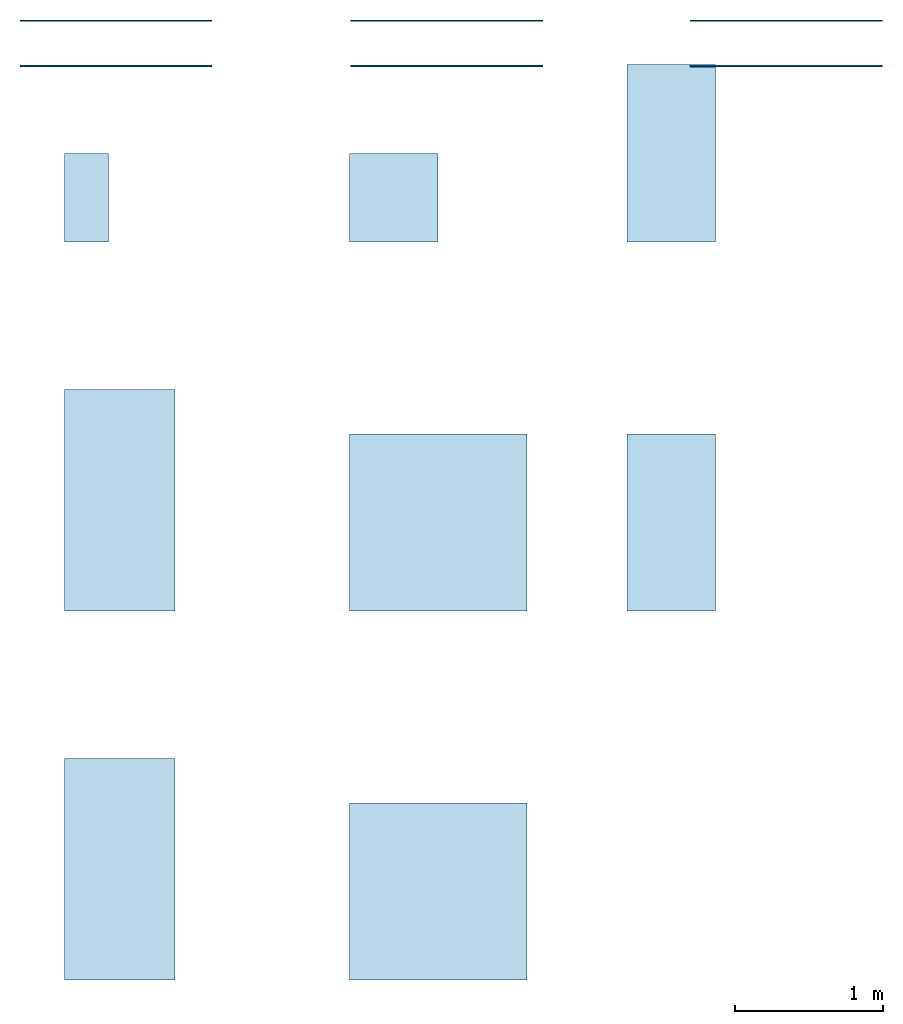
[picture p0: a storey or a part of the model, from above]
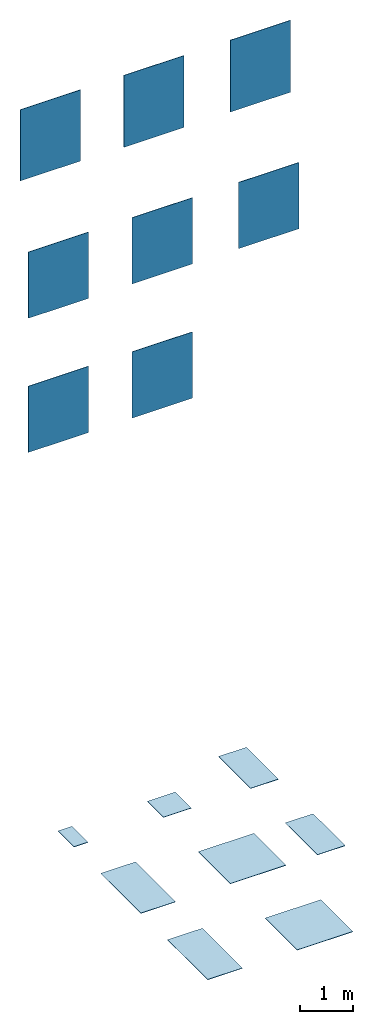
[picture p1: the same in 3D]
Properties of the parts of a building model (IFC2X3)

# File
Description: ViewDefinition [CoordinationView_V2.0], RevitIdentifiers [VersionGUID: 46d3328d-7286-4044-a276-93108096e048, NumberOfSaves: 353], CoordinateReference [CoordinateBase: Shared Coordinates, ProjectSite: Internal]
File name: Project Number
Time: 2025-03-24T15:53:54+01:00
Written by: ODA SDAI 24.3
Made in: Autodesk Revit 24.1.11.26 (ENU) - IFC 24.1.11.26

# IfcProject, Project Number
LongName: Refin-Blended; Phase: Project Status

# IfcSite, Default
RefLatitude: 51, 30, 0, 549316; RefLongitude: 0, -7, -34, -450321; RefElevation: 0 mm

# IfcBuilding
Pset_BuildingCommon - NumberOfStoreys: 1

# IfcBuildingStorey: Level:Circle Head - Project Datum (2)
Pset_AirSideSystemInformation - sets with these values: 2
Name | LongName = Name | Elevation (mm)
Level 0 | Level 0 | 0
Level 1 | Level 1 | 4000

# IfcSlab: Floor:Floor_Tiles_Refin-Etherea-Grey-120x120 RJ58, Floor:Floor_Tiles_Refin-Etherea-Grey-120x120 RJ58:357631
In: Level 0
Type - PredefinedType: FLOOR; Material: Etherea-Grey-120x120 RJ58 9 mm, <Unnamed> 1 mm
Type - Pset_ConcreteElementGeneral - FireRating: INERT
Type - Pset_ElementShading - Color: GREY
Type - Pset_FireRatingProperties - SurfaceSpreadOfFlame: INERT
Type - Pset_ManufacturerOccurrence - BarCode: N/A; SerialNumber: N/A
Type - Pset_ManufacturerTypeInformation - ArticleNumber: RJ58; ModelReference: RJ58; ModelLabel: GREY R 120X120; Manufacturer: info@refin.it; ProductionYear: N/A
Type - Pset_PrecastConcreteElementGeneral - SerialNumber: N/A
Type - Pset_ProductRequirements - Name: Etherea_Grey_120X120 R; Category: Pr_35_93_96_19:Ceramic tiles
Type - Pset_QuantityTakeOff - Reference: N/A
Type - Pset_ReinforcementBarPitchOfSlab - Description: PORCELAIN STONEWARE TILE; Reference: N/A
Type - Pset_SlabCommon - Reference: N/A; IsExternal: no; AcousticRating: N/A; FireRating: INERT; SurfaceSpreadOfFlame: INERT
Type - Pset_Warranty - WarrantyContent: N/A; Exclusions: N/A
Pset_QuantityTakeOff - sets with these values: 2
Pset_SlabCommon - LoadBearing: no; PitchAngle: 0 deg

# IfcSlab: Floor:Floor_Tiles_Refin-Etherea-Grey-30x60 RJ90, Floor:Floor_Tiles_Refin-Etherea-Grey-30x60 RJ90:304668
In: Level 0
Type - PredefinedType: FLOOR; Material: Etherea-Grey-30x60 RJ90 9 mm, <Unnamed> 1 mm
Type - Pset_ConcreteElementGeneral - FireRating: INERT
Type - Pset_ElementShading - Color: GREY
Type - Pset_FireRatingProperties - SurfaceSpreadOfFlame: INERT
Type - Pset_ManufacturerOccurrence - BarCode: N/A; SerialNumber: N/A
Type - Pset_ManufacturerTypeInformation - ArticleNumber: RJ90; ModelReference: RJ90; ModelLabel: GREY R 30X60; Manufacturer: info@refin.it; ProductionYear: N/A
Type - Pset_PrecastConcreteElementGeneral - SerialNumber: N/A
Type - Pset_ProductRequirements - Name: Etherea_Grey_30X60 R; Category: Pr_35_93_96_19:Ceramic tiles
Type - Pset_QuantityTakeOff - Reference: N/A
Type - Pset_ReinforcementBarPitchOfSlab - Description: PORCELAIN STONEWARE TILE; Reference: N/A
Type - Pset_SlabCommon - Reference: N/A; IsExternal: no; AcousticRating: N/A; FireRating: INERT; SurfaceSpreadOfFlame: INERT
Type - Pset_Warranty - WarrantyContent: N/A; Exclusions: N/A
Pset_QuantityTakeOff - sets with these values: 2
Pset_SlabCommon - LoadBearing: no; PitchAngle: 0 deg

# IfcSlab: Floor:Floor_Tiles_Refin-Etherea-Grey-60x120 RJ71, Floor:Floor_Tiles_Refin-Etherea-Grey-60x120 RJ71:357441
In: Level 0
Type - PredefinedType: FLOOR; Material: Etherea-Grey-60x120 RJ71 9 mm, <Unnamed> 1 mm
Type - Pset_ConcreteElementGeneral - FireRating: INERT
Type - Pset_ElementShading - Color: GREY
Type - Pset_FireRatingProperties - SurfaceSpreadOfFlame: INERT
Type - Pset_ManufacturerOccurrence - BarCode: N/A; SerialNumber: N/A
Type - Pset_ManufacturerTypeInformation - ArticleNumber: RJ71; ModelReference: RJ71; ModelLabel: GREY R 60X120; Manufacturer: info@refin.it; ProductionYear: N/A
Type - Pset_PrecastConcreteElementGeneral - SerialNumber: N/A
Type - Pset_ProductRequirements - Name: Etherea_Grey_60X120 R; Category: Pr_35_93_96_19:Ceramic tiles
Type - Pset_QuantityTakeOff - Reference: N/A
Type - Pset_ReinforcementBarPitchOfSlab - Description: PORCELAIN STONEWARE TILE; Reference: N/A
Type - Pset_SlabCommon - Reference: N/A; IsExternal: no; AcousticRating: N/A; FireRating: INERT; SurfaceSpreadOfFlame: INERT
Type - Pset_Warranty - WarrantyContent: N/A; Exclusions: N/A
Pset_QuantityTakeOff - sets with these values: 2
Pset_SlabCommon - LoadBearing: no; PitchAngle: 0 deg

# IfcSlab: Floor:Floor_Tiles_Refin-Etherea-Grey-60x60 RJ85, Floor:Floor_Tiles_Refin-Etherea-Grey-60x60 RJ85:357245
In: Level 0
Type - PredefinedType: FLOOR; Material: Etherea-Grey-60x60 RJ85 9 mm, <Unnamed> 1 mm
Type - Pset_ConcreteElementGeneral - FireRating: INERT
Type - Pset_ElementShading - Color: GREY
Type - Pset_FireRatingProperties - SurfaceSpreadOfFlame: INERT
Type - Pset_ManufacturerOccurrence - BarCode: N/A; SerialNumber: N/A
Type - Pset_ManufacturerTypeInformation - ArticleNumber: RJ85; ModelReference: RJ85; ModelLabel: GREY R 60X60; Manufacturer: info@refin.it; ProductionYear: N/A
Type - Pset_PrecastConcreteElementGeneral - SerialNumber: N/A
Type - Pset_ProductRequirements - Name: Etherea_Grey_60X60 R; Category: Pr_35_93_96_19:Ceramic tiles
Type - Pset_QuantityTakeOff - Reference: N/A
Type - Pset_ReinforcementBarPitchOfSlab - Description: PORCELAIN STONEWARE TILE; Reference: N/A
Type - Pset_SlabCommon - Reference: N/A; IsExternal: no; AcousticRating: N/A; FireRating: INERT; SurfaceSpreadOfFlame: INERT
Type - Pset_Warranty - WarrantyContent: N/A; Exclusions: N/A
Pset_QuantityTakeOff - sets with these values: 2
Pset_SlabCommon - LoadBearing: no; PitchAngle: 0 deg

# IfcSlab: Floor:Floor_Tiles_Refin-Etherea-Grey-75x150 RK14, Floor:Floor_Tiles_Refin-Etherea-Grey-75x150 RK14:357623
In: Level 0
Type - PredefinedType: FLOOR; Material: Etherea-Grey-75x150 RK14 9 mm, <Unnamed> 1 mm
Type - Pset_ConcreteElementGeneral - FireRating: INERT
Type - Pset_ElementShading - Color: GREY
Type - Pset_FireRatingProperties - SurfaceSpreadOfFlame: INERT
Type - Pset_ManufacturerOccurrence - BarCode: N/A; SerialNumber: N/A
Type - Pset_ManufacturerTypeInformation - ArticleNumber: RK14; ModelReference: RK14; ModelLabel: GREY R 75X150; Manufacturer: info@refin.it; ProductionYear: N/A
Type - Pset_PrecastConcreteElementGeneral - SerialNumber: N/A
Type - Pset_ProductRequirements - Name: Etherea_Grey_75X150 R; Category: Pr_35_93_96_19:Ceramic tiles
Type - Pset_QuantityTakeOff - Reference: N/A
Type - Pset_ReinforcementBarPitchOfSlab - Description: PORCELAIN STONEWARE TILE; Reference: N/A
Type - Pset_SlabCommon - Reference: N/A; IsExternal: no; AcousticRating: N/A; FireRating: INERT; SurfaceSpreadOfFlame: INERT
Type - Pset_Warranty - WarrantyContent: N/A; Exclusions: N/A
Pset_QuantityTakeOff - sets with these values: 2
Pset_SlabCommon - LoadBearing: no; PitchAngle: 0 deg

# IfcSlab: Floor:Floor_Tiles_Refin-Etherea-Grey-C2-GRIP-60x120 RN15, Floor:Floor_Tiles_Refin-Etherea-Grey-C2-GRIP-60x120 RN15:357639
In: Level 0
Type - PredefinedType: FLOOR; Material: Etherea-Grey-C2-GRIP-60x120 RN15 9 mm, <Unnamed> 1 mm
Type - Pset_ConcreteElementGeneral - FireRating: INERT
Type - Pset_ElementShading - Color: GREY
Type - Pset_FireRatingProperties - SurfaceSpreadOfFlame: INERT
Type - Pset_ManufacturerOccurrence - BarCode: N/A; SerialNumber: N/A
Type - Pset_ManufacturerTypeInformation - ArticleNumber: RN15; ModelReference: RN15; ModelLabel: GREY C2 GRIP R 60X120; Manufacturer: info@refin.it; ProductionYear: N/A
Type - Pset_PrecastConcreteElementGeneral - SerialNumber: N/A
Type - Pset_ProductRequirements - Name: Etherea_Grey_C2_GRIP_60X120 R; Category: Pr_35_93_96_19:Ceramic tiles
Type - Pset_QuantityTakeOff - Reference: N/A
Type - Pset_ReinforcementBarPitchOfSlab - Description: PORCELAIN STONEWARE TILE; Reference: N/A
Type - Pset_SlabCommon - Reference: N/A; IsExternal: no; AcousticRating: N/A; FireRating: INERT; SurfaceSpreadOfFlame: INERT
Type - Pset_Warranty - WarrantyContent: N/A; Exclusions: N/A
Pset_QuantityTakeOff - sets with these values: 2
Pset_SlabCommon - LoadBearing: no; PitchAngle: 0 deg

# IfcSlab: Floor:Floor_Tiles_Refin-Etherea-Grey-Lucido-120x120 RJ62, Floor:Floor_Tiles_Refin-Etherea-Grey-Lucido-120x120 RJ62:361557
In: Level 0
Type - PredefinedType: FLOOR; Material: Etherea-Grey-Lucido-120x120 RJ62 9 mm, <Unnamed> 1 mm
Type - Pset_ConcreteElementGeneral - FireRating: INERT
Type - Pset_ElementShading - Color: GREY
Type - Pset_FireRatingProperties - SurfaceSpreadOfFlame: INERT
Type - Pset_ManufacturerOccurrence - BarCode: N/A; SerialNumber: N/A
Type - Pset_ManufacturerTypeInformation - ArticleNumber: RJ62; ModelReference: RJ62; ModelLabel: GREY LUCIDO R 120X120; Manufacturer: info@refin.it; ProductionYear: N/A
Type - Pset_PrecastConcreteElementGeneral - SerialNumber: N/A
Type - Pset_ProductRequirements - Name: Etherea_Grey_Lucido_120X120 R; Category: Pr_35_93_96_19:Ceramic tiles
Type - Pset_QuantityTakeOff - Reference: N/A
Type - Pset_ReinforcementBarPitchOfSlab - Description: PORCELAIN STONEWARE TILE; Reference: N/A
Type - Pset_SlabCommon - Reference: N/A; IsExternal: no; AcousticRating: N/A; FireRating: INERT; SurfaceSpreadOfFlame: INERT
Type - Pset_Warranty - WarrantyContent: N/A; Exclusions: N/A
Pset_QuantityTakeOff - sets with these values: 2
Pset_SlabCommon - LoadBearing: no; PitchAngle: 0 deg

# IfcSlab: Floor:Floor_Tiles_Refin-Etherea-Grey-Lucido-75x150 RK19, Floor:Floor_Tiles_Refin-Etherea-Grey-Lucido-75x150 RK19:361417
In: Level 0
Type - PredefinedType: FLOOR; Material: Etherea-Grey-Lucido-75x150 RK19 9 mm, <Unnamed> 1 mm
Type - Pset_ConcreteElementGeneral - FireRating: INERT
Type - Pset_ElementShading - Color: GREY
Type - Pset_FireRatingProperties - SurfaceSpreadOfFlame: INERT
Type - Pset_ManufacturerOccurrence - BarCode: N/A; SerialNumber: N/A
Type - Pset_ManufacturerTypeInformation - ArticleNumber: RK19; ModelReference: RK19; ModelLabel: GREY LUCIDO R 75X150; Manufacturer: info@refin.it; ProductionYear: N/A
Type - Pset_PrecastConcreteElementGeneral - SerialNumber: N/A
Type - Pset_ProductRequirements - Name: Etherea_Grey_Lucido_75X150 R; Category: Pr_35_93_96_19:Ceramic tiles
Type - Pset_QuantityTakeOff - Reference: N/A
Type - Pset_ReinforcementBarPitchOfSlab - Description: PORCELAIN STONEWARE TILE; Reference: N/A
Type - Pset_SlabCommon - Reference: N/A; IsExternal: no; AcousticRating: N/A; FireRating: INERT; SurfaceSpreadOfFlame: INERT
Type - Pset_Warranty - WarrantyContent: N/A; Exclusions: N/A
Pset_QuantityTakeOff - sets with these values: 2
Pset_SlabCommon - LoadBearing: no; PitchAngle: 0 deg

# IfcWallStandardCase: Basic Wall:Wall_Tiles_Refin-Etherea-Grey-120x120 RJ58, Basic Wall:Wall_Tiles_Refin-Etherea-Grey-120x120 RJ58:335490
In: Level 0
Type - PredefinedType: STANDARD; Material: <Unnamed> 1 mm, Etherea-Grey-120x120 RJ58 9 mm
Type - Pset_ElementShading - Color: GREY
Type - Pset_FireRatingProperties - SurfaceSpreadOfFlame: INERT
Type - Pset_ManufacturerOccurrence - BarCode: N/A; SerialNumber: N/A
Type - Pset_ManufacturerTypeInformation - ArticleNumber: RJ58; ModelReference: RJ58; ModelLabel: GREY R 120X120; Manufacturer: info@refin.it; ProductionYear: N/A
Type - Pset_PrecastConcreteElementGeneral - SerialNumber: N/A
Type - Pset_ProductRequirements - Name: Etherea_Grey_120X120 R; Category: Pr_35_93_96_19:Ceramic tiles
Type - Pset_QuantityTakeOff - Reference: N/A
Type - Pset_ReinforcementBarPitchOfWall - Description: PORCELAIN STONEWARE TILE; Reference: N/A
Type - Pset_WallCommon - Reference: N/A; IsExternal: no; AcousticRating: N/A; SurfaceSpreadOfFlame: INERT
Type - Pset_Warranty - WarrantyContent: N/A; Exclusions: N/A
Pset_QuantityTakeOff - sets with these values: 2
Pset_WallCommon - LoadBearing: no; ExtendToStructure: no

# IfcWallStandardCase: Basic Wall:Wall_Tiles_Refin-Etherea-Grey-30x60 RJ90, Basic Wall:Wall_Tiles_Refin-Etherea-Grey-30x60 RJ90:334895
In: Level 0
Type - PredefinedType: STANDARD; Material: <Unnamed> 1 mm, Etherea-Grey-30x60 RJ90 9 mm
Type - Pset_ElementShading - Color: GREY
Type - Pset_FireRatingProperties - SurfaceSpreadOfFlame: INERT
Type - Pset_ManufacturerOccurrence - BarCode: N/A; SerialNumber: N/A
Type - Pset_ManufacturerTypeInformation - ArticleNumber: RJ90; ModelReference: RJ90; ModelLabel: GREY R 30X60; Manufacturer: info@refin.it; ProductionYear: N/A
Type - Pset_PrecastConcreteElementGeneral - SerialNumber: N/A
Type - Pset_ProductRequirements - Name: Etherea_Grey_30X60 R; Category: Pr_35_93_96_19:Ceramic tiles
Type - Pset_QuantityTakeOff - Reference: N/A
Type - Pset_ReinforcementBarPitchOfWall - Description: PORCELAIN STONEWARE TILE; Reference: N/A
Type - Pset_WallCommon - Reference: N/A; IsExternal: no; AcousticRating: N/A; SurfaceSpreadOfFlame: INERT
Type - Pset_Warranty - WarrantyContent: N/A; Exclusions: N/A
Pset_QuantityTakeOff - sets with these values: 2
Pset_WallCommon - LoadBearing: no; ExtendToStructure: no

# IfcWallStandardCase: Basic Wall:Wall_Tiles_Refin-Etherea-Grey-60x120 RJ71, Basic Wall:Wall_Tiles_Refin-Etherea-Grey-60x120 RJ71:334553
In: Level 0
Type - PredefinedType: STANDARD; Material: <Unnamed> 1 mm, Etherea-Grey-60x120 RJ71 9 mm
Type - Pset_ElementShading - Color: GREY
Type - Pset_FireRatingProperties - SurfaceSpreadOfFlame: INERT
Type - Pset_ManufacturerOccurrence - BarCode: N/A; SerialNumber: N/A
Type - Pset_ManufacturerTypeInformation - ArticleNumber: RJ71; ModelReference: RJ71; ModelLabel: GREY R 60X120; Manufacturer: info@refin.it; ProductionYear: N/A
Type - Pset_PrecastConcreteElementGeneral - SerialNumber: N/A
Type - Pset_ProductRequirements - Name: Etherea_Grey_60X120 R; Category: Pr_35_93_96_19:Ceramic tiles
Type - Pset_QuantityTakeOff - Reference: N/A
Type - Pset_ReinforcementBarPitchOfWall - Description: PORCELAIN STONEWARE TILE; Reference: N/A
Type - Pset_WallCommon - Reference: N/A; IsExternal: no; AcousticRating: N/A; SurfaceSpreadOfFlame: INERT
Type - Pset_Warranty - WarrantyContent: N/A; Exclusions: N/A
Pset_QuantityTakeOff - sets with these values: 2
Pset_WallCommon - LoadBearing: no; ExtendToStructure: no

# IfcWallStandardCase: Basic Wall:Wall_Tiles_Refin-Etherea-Grey-60x60 RJ85, Basic Wall:Wall_Tiles_Refin-Etherea-Grey-60x60 RJ85:333696
In: Level 0
Type - PredefinedType: STANDARD; Material: <Unnamed> 1 mm, Etherea-Grey-60x60 RJ85 9 mm
Type - Pset_ElementShading - Color: GREY
Type - Pset_FireRatingProperties - SurfaceSpreadOfFlame: INERT
Type - Pset_ManufacturerOccurrence - BarCode: N/A; SerialNumber: N/A
Type - Pset_ManufacturerTypeInformation - ArticleNumber: RJ85; ModelReference: RJ85; ModelLabel: GREY R 60X60; Manufacturer: info@refin.it; ProductionYear: N/A
Type - Pset_PrecastConcreteElementGeneral - SerialNumber: N/A
Type - Pset_ProductRequirements - Name: Etherea_Grey_60X60 R; Category: Pr_35_93_96_19:Ceramic tiles
Type - Pset_QuantityTakeOff - Reference: N/A
Type - Pset_ReinforcementBarPitchOfWall - Description: PORCELAIN STONEWARE TILE; Reference: N/A
Type - Pset_WallCommon - Reference: N/A; IsExternal: no; AcousticRating: N/A; SurfaceSpreadOfFlame: INERT
Type - Pset_Warranty - WarrantyContent: N/A; Exclusions: N/A
Pset_QuantityTakeOff - sets with these values: 2
Pset_WallCommon - LoadBearing: no; ExtendToStructure: no

# IfcWallStandardCase: Basic Wall:Wall_Tiles_Refin-Etherea-Grey-75x150 RK14, Basic Wall:Wall_Tiles_Refin-Etherea-Grey-75x150 RK14:335038
In: Level 0
Type - PredefinedType: STANDARD; Material: <Unnamed> 1 mm, Etherea-Grey-75x150 RK14 9 mm
Type - Pset_ElementShading - Color: GREY
Type - Pset_FireRatingProperties - SurfaceSpreadOfFlame: INERT
Type - Pset_ManufacturerOccurrence - BarCode: N/A; SerialNumber: N/A
Type - Pset_ManufacturerTypeInformation - ArticleNumber: RK14; ModelReference: RK14; ModelLabel: GREY R 75X150; Manufacturer: info@refin.it; ProductionYear: N/A
Type - Pset_PrecastConcreteElementGeneral - SerialNumber: N/A
Type - Pset_ProductRequirements - Name: Etherea_Grey_75X150 R; Category: Pr_35_93_96_19:Ceramic tiles
Type - Pset_QuantityTakeOff - Reference: N/A
Type - Pset_ReinforcementBarPitchOfWall - Description: PORCELAIN STONEWARE TILE; Reference: N/A
Type - Pset_WallCommon - Reference: N/A; IsExternal: no; AcousticRating: N/A; SurfaceSpreadOfFlame: INERT
Type - Pset_Warranty - WarrantyContent: N/A; Exclusions: N/A
Pset_QuantityTakeOff - sets with these values: 2
Pset_WallCommon - LoadBearing: no; ExtendToStructure: no

# IfcWallStandardCase: Basic Wall:Wall_Tiles_Refin-Etherea-Grey-C2-GRIP-60x120 RN15, Basic Wall:Wall_Tiles_Refin-Etherea-Grey-C2-GRIP-60x120 RN15:335882
In: Level 0
Type - PredefinedType: STANDARD; Material: <Unnamed> 1 mm, Etherea-Grey-C2-GRIP-60x120 RN15 9 mm
Type - Pset_ElementShading - Color: GREY
Type - Pset_FireRatingProperties - SurfaceSpreadOfFlame: INERT
Type - Pset_ManufacturerOccurrence - BarCode: N/A; SerialNumber: N/A
Type - Pset_ManufacturerTypeInformation - ArticleNumber: RN15; ModelReference: RN15; ModelLabel: GREY C2 GRIP R 60X120; Manufacturer: info@refin.it; ProductionYear: N/A
Type - Pset_PrecastConcreteElementGeneral - SerialNumber: N/A
Type - Pset_ProductRequirements - Name: Etherea_Grey_C2_GRIP_60X120 R; Category: Pr_35_93_96_19:Ceramic tiles
Type - Pset_QuantityTakeOff - Reference: N/A
Type - Pset_ReinforcementBarPitchOfWall - Description: PORCELAIN STONEWARE TILE; Reference: N/A
Type - Pset_WallCommon - Reference: N/A; IsExternal: no; AcousticRating: N/A; SurfaceSpreadOfFlame: INERT
Type - Pset_Warranty - WarrantyContent: N/A; Exclusions: N/A
Pset_QuantityTakeOff - sets with these values: 2
Pset_WallCommon - LoadBearing: no; ExtendToStructure: no

# IfcWallStandardCase: Basic Wall:Wall_Tiles_Refin-Etherea-Grey-Lucido-120x120 RJ62, Basic Wall:Wall_Tiles_Refin-Etherea-Grey-Lucido-120x120 RJ62:352457
In: Level 0
Type - PredefinedType: STANDARD; Material: <Unnamed> 1 mm, Etherea-Grey-Lucido-120x120 RJ62 9 mm
Type - Pset_ElementShading - Color: GREY
Type - Pset_FireRatingProperties - SurfaceSpreadOfFlame: INERT
Type - Pset_ManufacturerOccurrence - BarCode: N/A; SerialNumber: N/A
Type - Pset_ManufacturerTypeInformation - ArticleNumber: RJ62; ModelReference: RJ62; ModelLabel: GREY LUCIDO R 120X120; Manufacturer: info@refin.it; ProductionYear: N/A
Type - Pset_PrecastConcreteElementGeneral - SerialNumber: N/A
Type - Pset_ProductRequirements - Name: Etherea_Grey_Lucido_120X120 R; Category: Pr_35_93_96_19:Ceramic tiles
Type - Pset_QuantityTakeOff - Reference: N/A
Type - Pset_ReinforcementBarPitchOfWall - Description: PORCELAIN STONEWARE TILE; Reference: N/A
Type - Pset_WallCommon - Reference: N/A; IsExternal: no; AcousticRating: N/A; SurfaceSpreadOfFlame: INERT
Type - Pset_Warranty - WarrantyContent: N/A; Exclusions: N/A
Pset_QuantityTakeOff - sets with these values: 2
Pset_WallCommon - LoadBearing: no; ExtendToStructure: no

# IfcWallStandardCase: Basic Wall:Wall_Tiles_Refin-Etherea-Grey-Lucido-75x150 RK19, Basic Wall:Wall_Tiles_Refin-Etherea-Grey-Lucido-75x150 RK19:352136
In: Level 0
Type - PredefinedType: STANDARD; Material: <Unnamed> 1 mm, Etherea-Grey-Lucido-75x150 RK19 9 mm
Type - Pset_ElementShading - Color: GREY
Type - Pset_FireRatingProperties - SurfaceSpreadOfFlame: INERT
Type - Pset_ManufacturerOccurrence - BarCode: N/A; SerialNumber: N/A
Type - Pset_ManufacturerTypeInformation - ArticleNumber: RK19; ModelReference: RK19; ModelLabel: GREY LUCIDO R 75X150; Manufacturer: info@refin.it; ProductionYear: N/A
Type - Pset_PrecastConcreteElementGeneral - SerialNumber: N/A
Type - Pset_ProductRequirements - Name: Etherea_Grey_Lucido_75X150 R; Category: Pr_35_93_96_19:Ceramic tiles
Type - Pset_QuantityTakeOff - Reference: N/A
Type - Pset_ReinforcementBarPitchOfWall - Description: PORCELAIN STONEWARE TILE; Reference: N/A
Type - Pset_WallCommon - Reference: N/A; IsExternal: no; AcousticRating: N/A; SurfaceSpreadOfFlame: INERT
Type - Pset_Warranty - WarrantyContent: N/A; Exclusions: N/A
Pset_QuantityTakeOff - sets with these values: 2
Pset_WallCommon - LoadBearing: no; ExtendToStructure: no
